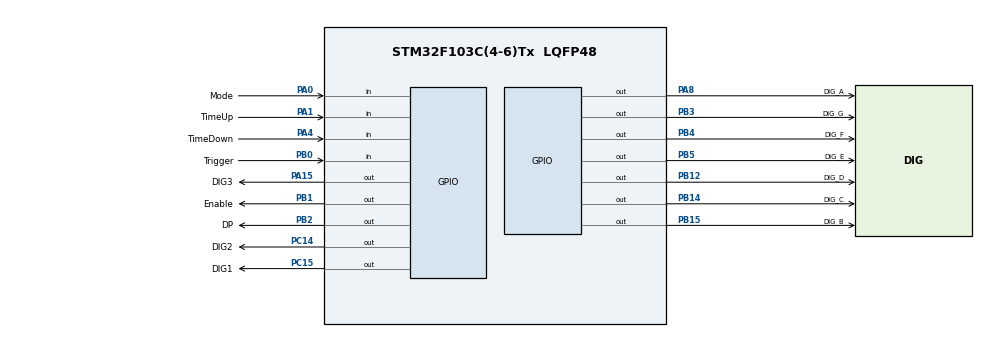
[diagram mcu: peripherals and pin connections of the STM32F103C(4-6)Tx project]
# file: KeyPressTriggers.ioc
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IWDG.Prescaler=IWDG_PRESCALER_64
IWDG.Reload=625
Mcu.Family=STM32F1
Mcu.Name=STM32F103C(4-6)Tx
Mcu.Package=LQFP48
NVIC.PriorityGroup=NVIC_PRIORITYGROUP_4
NVIC.TIM2_IRQn=true\:0\:0\:false\:false\:true\:true\:true\:true
PA0-WKUP.GPIO_Label=Mode
PA0-WKUP.GPIO_PuPd=GPIO_PULLUP
PA0-WKUP.Signal=GPIO_Input
PA1.GPIO_Label=TimeUp
PA1.GPIO_PuPd=GPIO_PULLUP
PA1.Signal=GPIO_Input
PA13.Mode=Serial_Wire
PA13.Signal=SYS_JTMS-SWDIO
PA14.Mode=Serial_Wire
PA14.Signal=SYS_JTCK-SWCLK
PA15.GPIO_Label=DIG3
PA15.Signal=GPIO_Output
PA4.GPIO_Label=TimeDown
PA4.GPIO_PuPd=GPIO_PULLUP
PA4.Signal=GPIO_Input
PA8.GPIO_Label=DIG_A
PA8.Signal=GPIO_Output
PB0.GPIO_Label=Trigger
PB0.GPIO_PuPd=GPIO_PULLUP
PB0.Signal=GPIO_Input
PB1.GPIO_Label=Enable
PB1.Signal=GPIO_Output
PB12.GPIO_Label=DIG_D
PB12.Signal=GPIO_Output
PB14.GPIO_Label=DIG_C
PB14.Signal=GPIO_Output
PB15.GPIO_Label=DIG_B
PB15.Signal=GPIO_Output
PB2.GPIO_Label=DP
PB2.Signal=GPIO_Output
PB3.GPIO_Label=DIG_G
PB3.Signal=GPIO_Output
PB4.GPIO_Label=DIG_F
PB4.Signal=GPIO_Output
PB5.GPIO_Label=DIG_E
PB5.Signal=GPIO_Output
PC14-OSC32_IN.GPIO_Label=DIG2
PC14-OSC32_IN.Signal=GPIO_Output
PC15-OSC32_OUT.GPIO_Label=DIG1
PC15-OSC32_OUT.Signal=GPIO_Output
PD0-OSC_IN.Mode=HSE-External-Oscillator
PD0-OSC_IN.Signal=RCC_OSC_IN
PD1-OSC_OUT.Mode=HSE-External-Oscillator
PD1-OSC_OUT.Signal=RCC_OSC_OUT
ProjectManager.HeapSize=0x200
ProjectManager.StackSize=0x400
ProjectManager.TargetToolchain=STM32CubeIDE
RCC.AHBFreq_Value=72000000
RCC.APB1CLKDivider=RCC_HCLK_DIV2
RCC.APB1Freq_Value=36000000
RCC.APB1TimFreq_Value=72000000
RCC.APB2Freq_Value=72000000
RCC.APB2TimFreq_Value=72000000
RCC.HCLKFreq_Value=72000000
RCC.PLLMUL=RCC_PLL_MUL9
RCC.PLLSourceVirtual=RCC_PLLSOURCE_HSE
RCC.SYSCLKFreq_VALUE=72000000
RCC.SYSCLKSource=RCC_SYSCLKSOURCE_PLLCLK
RCC.USBFreq_Value=72000000
TIM2.AutoReloadPreload=TIM_AUTORELOAD_PRELOAD_ENABLE
TIM2.Period=999
TIM2.Prescaler=71
VP_IWDG_VS_IWDG.Mode=IWDG_Activate
VP_TIM2_VS_ClockSourceINT.Mode=Internal
board=custom

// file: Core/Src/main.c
/* USER CODE BEGIN Header */
/**
  ******************************************************************************
  * @file           : main.c
  * @brief          : Main program body
  ******************************************************************************
  * @attention
  *
  * Copyright (c) 2023 STMicroelectronics.
  * All rights reserved.
  *
  * This software is licensed under terms that can be found in the LICENSE file
  * in the root directory of this software component.
  * If no LICENSE file comes with this software, it is provided AS-IS.
  *
  ******************************************************************************
  */
/* USER CODE END Header */
#include "main.h"
#include "iwdg.h"
#include "tim.h"
#include "gpio.h"

void SystemClock_Config(void);

int main(void)
{

  /* MCU Configuration--------------------------------------------------------*/

  /* Reset of all peripherals, Initializes the Flash interface and the Systick. */
  HAL_Init();

  /* Configure the system clock */
  SystemClock_Config();

  /* Initialize all configured peripherals */
  MX_GPIO_Init();
  MX_IWDG_Init();
  MX_TIM2_Init();

  /* Infinite loop */
  while (1)
  {

  }
}

void SystemClock_Config(void)
{
  RCC_OscInitTypeDef RCC_OscInitStruct = {0};
  RCC_ClkInitTypeDef RCC_ClkInitStruct = {0};

  /** Initializes the RCC Oscillators according to the specified parameters
  * in the RCC_OscInitTypeDef structure.
  */
  RCC_OscInitStruct.OscillatorType = RCC_OSCILLATORTYPE_HSI|RCC_OSCILLATORTYPE_LSI;
  RCC_OscInitStruct.HSIState = RCC_HSI_ON;
  RCC_OscInitStruct.HSICalibrationValue = RCC_HSICALIBRATION_DEFAULT;
  RCC_OscInitStruct.LSIState = RCC_LSI_ON;
  RCC_OscInitStruct.PLL.PLLState = RCC_PLL_ON;
  RCC_OscInitStruct.PLL.PLLSource = RCC_PLLSOURCE_HSI_DIV2;
  RCC_OscInitStruct.PLL.PLLMUL = RCC_PLL_MUL16;
  if (HAL_RCC_OscConfig(&RCC_OscInitStruct) != HAL_OK)
  {
    Error_Handler();
  }

  /** Initializes the CPU, AHB and APB buses clocks
  */
  RCC_ClkInitStruct.ClockType = RCC_CLOCKTYPE_HCLK|RCC_CLOCKTYPE_SYSCLK
                              |RCC_CLOCKTYPE_PCLK1|RCC_CLOCKTYPE_PCLK2;
  RCC_ClkInitStruct.SYSCLKSource = RCC_SYSCLKSOURCE_PLLCLK;
  RCC_ClkInitStruct.AHBCLKDivider = RCC_SYSCLK_DIV1;
  RCC_ClkInitStruct.APB1CLKDivider = RCC_HCLK_DIV2;
  RCC_ClkInitStruct.APB2CLKDivider = RCC_HCLK_DIV1;

  if (HAL_RCC_ClockConfig(&RCC_ClkInitStruct, FLASH_LATENCY_2) != HAL_OK)
  {
    Error_Handler();
  }
}

void Error_Handler(void)
{
  __disable_irq();
  while (1)
  {
  }
}
